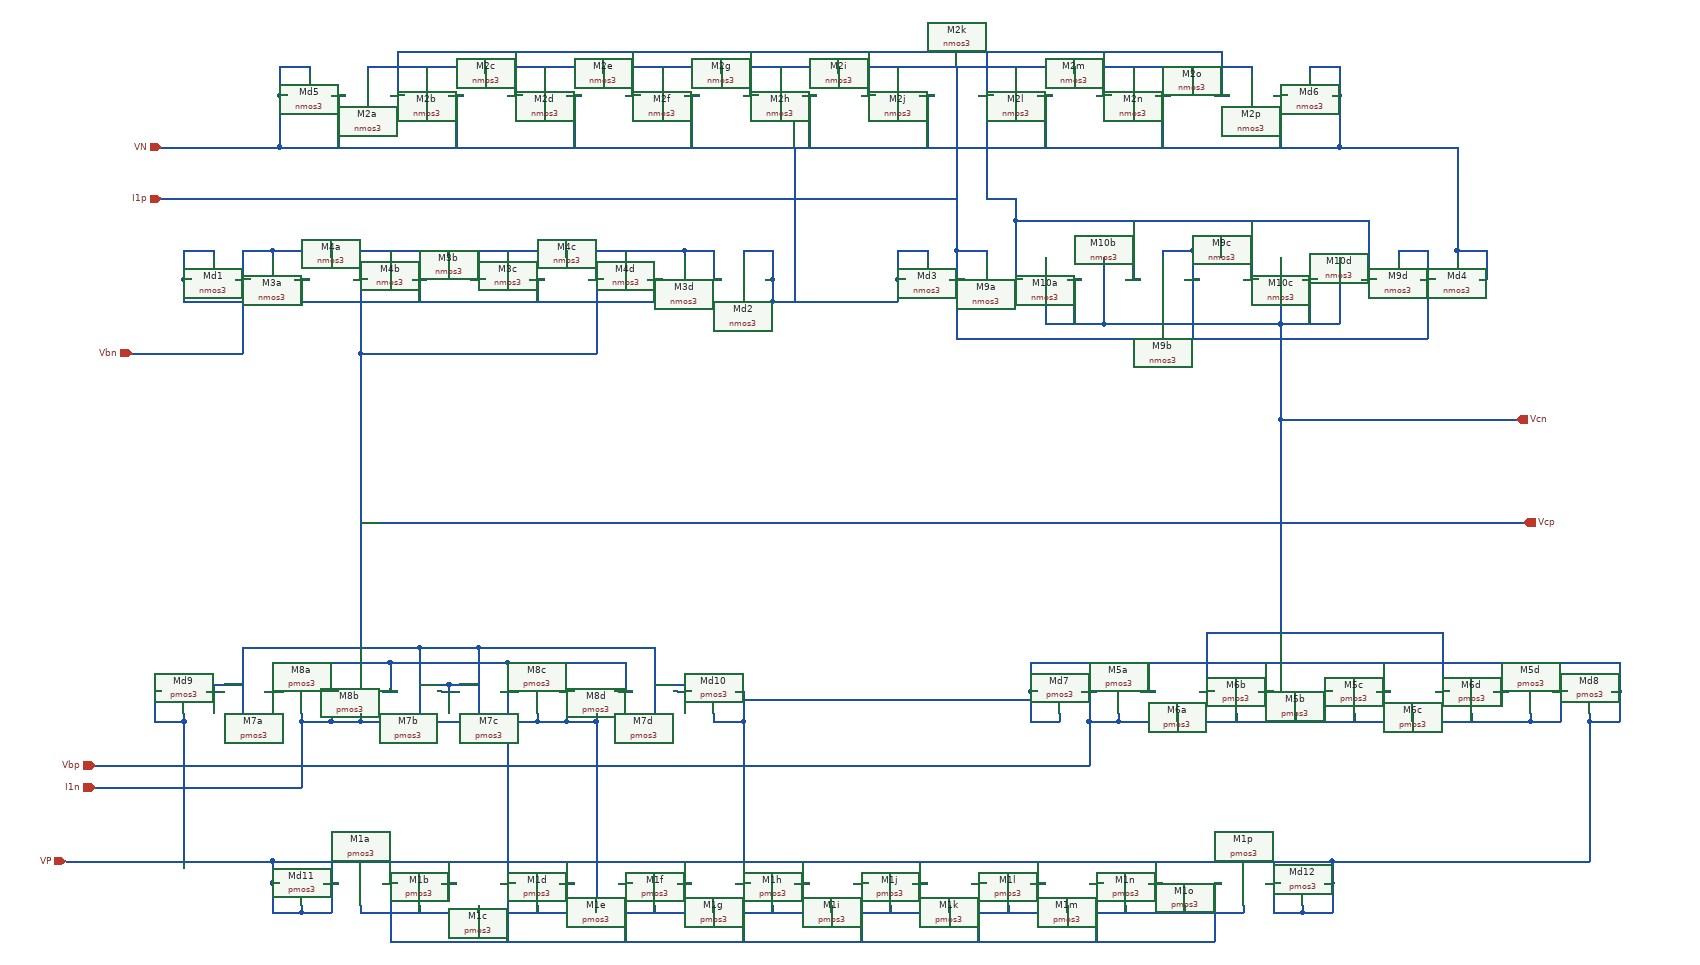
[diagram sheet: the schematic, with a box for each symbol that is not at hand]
v {xschem version=2.9.9 file_version=1.2 }
G {}
K {}
V {}
S {}
E {}
N 580 -1780 600 -1780 { lab=I1p}
N 660 -1780 680 -1780 { lab=Vcp}
N 740 -1780 760 -1780 { lab=I1p}
N 820 -1780 840 -1780 { lab=Vbn}
N 900 -1780 920 -1780 { lab=I1p}
N 980 -1780 1000 -1780 { lab=Vcp}
N 1060 -1780 1080 -1780 { lab=I1p}
N 550 -1820 550 -1810 { lab=Vbn}
N 630 -1820 630 -1810 { lab=Vbn}
N 710 -1820 710 -1810 { lab=Vbn}
N 790 -1820 790 -1810 { lab=Vbn}
N 870 -1820 870 -1810 { lab=Vbn}
N 950 -1820 950 -1810 { lab=Vbn}
N 1030 -1820 1030 -1810 { lab=Vbn}
N 1110 -1820 1110 -1810 { lab=Vbn}
N 550 -1820 1110 -1820 { lab=Vbn}
N 500 -1780 520 -1780 { lab=Vbn}
N 510 -1820 510 -1780 { lab=Vbn}
N 510 -1820 550 -1820 { lab=Vbn}
N 590 -1780 590 -1750 { lab=I1p}
N 750 -1780 750 -1750 { lab=I1p}
N 910 -1780 910 -1750 { lab=I1p}
N 830 -1820 830 -1780 { lab=Vbn}
N 1070 -1780 1070 -1750 { lab=I1p}
N 1140 -1780 1160 -1780 { lab=Vbn}
N 1150 -1820 1150 -1780 { lab=Vbn}
N 1110 -1820 1150 -1820 { lab=Vbn}
N 1190 -1820 1190 -1810 { lab=I1p}
N 1190 -1820 1230 -1820 { lab=I1p}
N 1230 -1820 1230 -1780 { lab=I1p}
N 1220 -1780 1230 -1780 { lab=I1p}
N 430 -1780 440 -1780 { lab=I1p}
N 430 -1820 430 -1780 { lab=I1p}
N 430 -1820 470 -1820 { lab=I1p}
N 470 -1820 470 -1810 { lab=I1p}
N 430 -1780 430 -1750 { lab=I1p}
N 1230 -1780 1230 -1750 { lab=I1p}
N 1550 -1780 1570 -1780 { lab=#net1}
N 1630 -1780 1650 -1780 { lab=Vcn}
N 1710 -1780 1730 -1780 { lab=#net1}
N 1790 -1780 1810 -1780 { lab=I1p}
N 1870 -1780 1890 -1780 { lab=#net1}
N 1950 -1780 1970 -1780 { lab=Vcn}
N 2030 -1780 2050 -1780 { lab=#net1}
N 1470 -1780 1490 -1780 { lab=I1p}
N 2110 -1780 2130 -1780 { lab=I1p}
N 2160 -1820 2160 -1810 { lab=I1p}
N 2160 -1820 2200 -1820 { lab=I1p}
N 2200 -1820 2200 -1780 { lab=I1p}
N 2190 -1780 2200 -1780 { lab=I1p}
N 1400 -1780 1410 -1780 { lab=I1p}
N 1400 -1820 1400 -1780 { lab=I1p}
N 1400 -1820 1440 -1820 { lab=I1p}
N 1440 -1820 1440 -1810 { lab=I1p}
N 1400 -1780 1400 -1750 { lab=I1p}
N 670 -1780 670 -1680 { lab=Vcp}
N 990 -1780 990 -1680 { lab=Vcp}
N 670 -1680 990 -1680 { lab=Vcp}
N 1560 -1860 2040 -1860 { lab=#net1}
N 1560 -1890 1560 -1860 { lab=#net1}
N 1520 -1820 1520 -1810 { lab=I1p}
N 1760 -1820 1760 -1810 { lab=I1p}
N 1840 -1820 1840 -1810 { lab=I1p}
N 2080 -1820 2080 -1810 { lab=I1p}
N 1600 -1810 1600 -1720 { lab=Vcn}
N 1600 -1720 1680 -1720 { lab=Vcn}
N 1680 -1810 1680 -1720 { lab=Vcn}
N 1920 -1810 1920 -1720 { lab=Vcn}
N 1920 -1720 2000 -1720 { lab=Vcn}
N 2000 -1810 2000 -1720 { lab=Vcn}
N 1680 -1720 1920 -1720 { lab=Vcn}
N 1920 -1720 1920 -1590 { lab=Vcn}
N 1920 -1590 2240 -1590 { lab=Vcn}
N 1560 -1860 1560 -1780 { lab=#net1}
N 1720 -1860 1720 -1780 { lab=#net1}
N 1880 -1860 1880 -1780 { lab=#net1}
N 2040 -1860 2040 -1780 { lab=#net1}
N 710 -2030 730 -2030 { lab=#net1}
N 790 -2030 810 -2030 { lab=I1p}
N 870 -2030 890 -2030 { lab=#net1}
N 950 -2030 970 -2030 { lab=I1p}
N 1030 -2030 1050 -2030 { lab=#net1}
N 1110 -2030 1130 -2030 { lab=I1p}
N 1190 -2030 1210 -2030 { lab=#net1}
N 1270 -2030 1290 -2030 { lab=I1p}
N 1350 -2030 1370 -2030 { lab=#net1}
N 1430 -2030 1450 -2030 { lab=I1p}
N 1510 -2030 1530 -2030 { lab=#net1}
N 1590 -2030 1610 -2030 { lab=I1p}
N 1670 -2030 1690 -2030 { lab=#net1}
N 1750 -2030 1770 -2030 { lab=I1p}
N 1830 -2030 1850 -2030 { lab=#net1}
N 680 -2070 680 -2060 { lab=I1p}
N 760 -2070 760 -2060 { lab=I1p}
N 840 -2070 840 -2060 { lab=I1p}
N 920 -2070 920 -2060 { lab=I1p}
N 1000 -2070 1000 -2060 { lab=I1p}
N 1080 -2070 1080 -2060 { lab=I1p}
N 1160 -2070 1160 -2060 { lab=I1p}
N 1240 -2070 1240 -2060 { lab=I1p}
N 1320 -2070 1320 -2060 { lab=I1p}
N 1400 -2070 1400 -2060 { lab=I1p}
N 1480 -2070 1480 -2060 { lab=I1p}
N 1560 -2070 1560 -2060 { lab=I1p}
N 1640 -2070 1640 -2060 { lab=I1p}
N 1720 -2070 1720 -2060 { lab=I1p}
N 1800 -2070 1800 -2060 { lab=I1p}
N 1880 -2070 1880 -2060 { lab=I1p}
N 680 -2070 1880 -2070 { lab=I1p}
N 640 -2030 640 -1960 { lab=I1p}
N 960 -2030 960 -1960 { lab=I1p}
N 1120 -2030 1120 -1960 { lab=I1p}
N 1280 -2030 1280 -1960 { lab=I1p}
N 1440 -2030 1440 -1960 { lab=I1p}
N 1600 -2030 1600 -1960 { lab=I1p}
N 1760 -2030 1760 -1960 { lab=I1p}
N 630 -2030 650 -2030 { lab=I1p}
N 600 -2070 600 -2060 { lab=I1p}
N 560 -2070 600 -2070 { lab=I1p}
N 560 -2070 560 -2030 { lab=I1p}
N 560 -2030 570 -2030 { lab=I1p}
N 560 -2030 560 -1960 { lab=I1p}
N 1910 -2030 1930 -2030 { lab=I1p}
N 1960 -2070 1960 -2060 { lab=I1p}
N 1960 -2070 2000 -2070 { lab=I1p}
N 2000 -2070 2000 -2030 { lab=I1p}
N 1990 -2030 2000 -2030 { lab=I1p}
N 2000 -2030 2000 -1960 { lab=I1p}
N 1480 -1700 2120 -1700 { lab=I1p}
N 1800 -1780 1800 -1700 { lab=I1p}
N 1480 -1780 1480 -1700 { lab=I1p}
N 2120 -1780 2120 -1700 { lab=I1p}
N 1760 -1820 1800 -1820 { lab=I1p}
N 1800 -1820 1800 -1780 { lab=I1p}
N 1800 -1820 1840 -1820 { lab=I1p}
N 2080 -1820 2120 -1820 { lab=I1p}
N 2120 -1820 2120 -1780 { lab=I1p}
N 1480 -1820 1520 -1820 { lab=I1p}
N 1480 -1820 1480 -1780 { lab=I1p}
N 1480 -2060 1480 -1910 { lab=I1p}
N 1640 -1780 1640 -1720 { lab=Vcn}
N 1960 -1780 1960 -1720 { lab=Vcn}
N 1730 -1220 1750 -1220 { lab=VP}
N 1700 -1190 1700 -1180 { lab=Vbp}
N 1780 -1190 1780 -1180 { lab=Vbp}
N 1810 -1220 1830 -1220 { lab=Vcn}
N 1890 -1220 1910 -1220 { lab=VP}
N 1860 -1190 1860 -1180 { lab=Vbp}
N 1940 -1190 1940 -1180 { lab=Vbp}
N 1970 -1220 1990 -1220 { lab=Vbp}
N 2050 -1220 2070 -1220 { lab=VP}
N 2020 -1190 2020 -1180 { lab=Vbp}
N 2100 -1190 2100 -1180 { lab=Vbp}
N 2130 -1220 2150 -1220 { lab=Vcn}
N 2210 -1220 2230 -1220 { lab=VP}
N 2180 -1190 2180 -1180 { lab=Vbp}
N 2260 -1190 2260 -1180 { lab=Vbp}
N 2290 -1220 2310 -1220 { lab=Vbp}
N 1700 -1180 2260 -1180 { lab=Vbp}
N 1650 -1220 1670 -1220 { lab=Vbp}
N 1580 -1220 1590 -1220 { lab=VP}
N 2370 -1220 2380 -1220 { lab=VP}
N 1580 -1220 1580 -1180 { lab=VP}
N 1580 -1180 1620 -1180 { lab=VP}
N 1620 -1190 1620 -1180 { lab=VP}
N 1580 -1260 1580 -1220 { lab=VP}
N 2340 -1190 2340 -1180 { lab=VP}
N 2340 -1180 2380 -1180 { lab=VP}
N 2380 -1220 2380 -1180 { lab=VP}
N 2380 -1260 2380 -1220 { lab=VP}
N 1740 -1260 1740 -1220 { lab=VP}
N 1900 -1260 1900 -1220 { lab=VP}
N 1820 -1300 1820 -1220 { lab=Vcn}
N 2060 -1260 2060 -1220 { lab=VP}
N 2140 -1300 2140 -1220 { lab=Vcn}
N 2220 -1260 2220 -1220 { lab=VP}
N 1660 -1220 1660 -1180 { lab=Vbp}
N 1660 -1180 1700 -1180 { lab=Vbp}
N 2300 -1220 2300 -1180 { lab=Vbp}
N 2260 -1180 2300 -1180 { lab=Vbp}
N 1980 -1220 1980 -1180 { lab=Vbp}
N 1660 -1180 1660 -1120 { lab=Vbp}
N 540 -1220 560 -1220 { lab=#net2}
N 620 -1220 640 -1220 { lab=I1n}
N 700 -1220 720 -1220 { lab=#net2}
N 780 -1220 800 -1220 { lab=Vcp}
N 860 -1220 880 -1220 { lab=#net2}
N 940 -1220 960 -1220 { lab=I1n}
N 1020 -1220 1040 -1220 { lab=#net2}
N 1100 -1220 1120 -1220 { lab=Vcp}
N 460 -1220 480 -1220 { lab=Vcp}
N 390 -1220 400 -1220 { lab=VP}
N 1180 -1220 1190 -1220 { lab=VP}
N 390 -1220 390 -1180 { lab=VP}
N 390 -1180 430 -1180 { lab=VP}
N 430 -1190 430 -1180 { lab=VP}
N 1150 -1190 1150 -1180 { lab=VP}
N 1150 -1180 1190 -1180 { lab=VP}
N 1190 -1220 1190 -1180 { lab=VP}
N 590 -1190 590 -1180 { lab=I1n}
N 910 -1190 910 -1180 { lab=I1n}
N 910 -1180 950 -1180 { lab=I1n}
N 990 -1190 990 -1180 { lab=I1n}
N 950 -1180 990 -1180 { lab=I1n}
N 670 -1190 670 -1180 { lab=I1n}
N 630 -1180 670 -1180 { lab=I1n}
N 590 -1180 630 -1180 { lab=I1n}
N 510 -1280 510 -1190 { lab=Vcp}
N 510 -1280 750 -1280 { lab=Vcp}
N 750 -1280 750 -1190 { lab=Vcp}
N 830 -1280 830 -1190 { lab=Vcp}
N 750 -1280 830 -1280 { lab=Vcp}
N 1070 -1280 1070 -1190 { lab=Vcp}
N 830 -1280 1070 -1280 { lab=Vcp}
N 470 -1230 470 -1220 { lab=Vcp}
N 470 -1230 510 -1230 { lab=Vcp}
N 790 -1230 790 -1220 { lab=Vcp}
N 750 -1230 790 -1230 { lab=Vcp}
N 790 -1230 830 -1230 { lab=Vcp}
N 1110 -1230 1110 -1220 { lab=Vcp}
N 1070 -1230 1110 -1230 { lab=Vcp}
N 710 -1260 710 -1220 { lab=#net2}
N 550 -1260 710 -1260 { lab=#net2}
N 550 -1260 550 -1220 { lab=#net2}
N 870 -1260 870 -1220 { lab=#net2}
N 870 -1260 1030 -1260 { lab=#net2}
N 1030 -1260 1030 -1220 { lab=#net2}
N 710 -1260 870 -1260 { lab=#net2}
N 670 -930 670 -920 { lab=I1n}
N 700 -960 720 -960 { lab=#net2}
N 750 -930 750 -920 { lab=I1n}
N 780 -960 800 -960 { lab=VP}
N 830 -930 830 -920 { lab=I1n}
N 860 -960 880 -960 { lab=#net2}
N 910 -930 910 -920 { lab=I1n}
N 940 -960 960 -960 { lab=VP}
N 990 -930 990 -920 { lab=I1n}
N 1020 -960 1040 -960 { lab=#net2}
N 1070 -930 1070 -920 { lab=I1n}
N 1100 -960 1120 -960 { lab=VP}
N 1150 -930 1150 -920 { lab=I1n}
N 1180 -960 1200 -960 { lab=#net2}
N 1230 -930 1230 -920 { lab=I1n}
N 1260 -960 1280 -960 { lab=VP}
N 1310 -930 1310 -920 { lab=I1n}
N 1340 -960 1360 -960 { lab=#net2}
N 1390 -930 1390 -920 { lab=I1n}
N 1420 -960 1440 -960 { lab=VP}
N 1470 -930 1470 -920 { lab=I1n}
N 1500 -960 1520 -960 { lab=#net2}
N 1550 -930 1550 -920 { lab=I1n}
N 1580 -960 1600 -960 { lab=VP}
N 1630 -930 1630 -920 { lab=I1n}
N 1660 -960 1680 -960 { lab=#net2}
N 1710 -930 1710 -920 { lab=I1n}
N 1740 -960 1760 -960 { lab=VP}
N 1790 -930 1790 -920 { lab=I1n}
N 1820 -960 1840 -960 { lab=#net2}
N 1870 -930 1870 -920 { lab=I1n}
N 1900 -960 1920 -960 { lab=VP}
N 670 -920 1870 -920 { lab=I1n}
N 620 -960 640 -960 { lab=VP}
N 710 -960 710 -880 { lab=#net2}
N 790 -990 790 -960 { lab=VP}
N 870 -960 870 -880 { lab=#net2}
N 950 -990 950 -960 { lab=VP}
N 1030 -960 1030 -880 { lab=#net2}
N 1110 -990 1110 -960 { lab=VP}
N 1190 -960 1190 -880 { lab=#net2}
N 1270 -990 1270 -960 { lab=VP}
N 1350 -960 1350 -880 { lab=#net2}
N 1430 -990 1430 -960 { lab=VP}
N 1510 -960 1510 -880 { lab=#net2}
N 1590 -990 1590 -960 { lab=VP}
N 1670 -960 1670 -880 { lab=#net2}
N 1750 -990 1750 -960 { lab=VP}
N 1830 -960 1830 -880 { lab=#net2}
N 630 -1220 630 -1180 { lab=I1n}
N 950 -1220 950 -1180 { lab=I1n}
N 670 -1180 910 -1180 { lab=I1n}
N 990 -1180 990 -1110 { lab=I1n}
N 710 -880 1830 -880 { lab=#net2}
N 310 -1090 590 -1090 { lab=I1n}
N 400 -1890 1480 -1890 { lab=I1p}
N 1950 -930 1950 -920 { lab=VP}
N 1950 -920 1980 -920 { lab=VP}
N 1980 -920 1990 -920 { lab=VP}
N 1990 -960 1990 -920 { lab=VP}
N 1980 -960 1990 -960 { lab=VP}
N 1990 -990 1990 -960 { lab=VP}
N 590 -930 590 -920 { lab=VP}
N 550 -920 590 -920 { lab=VP}
N 550 -960 550 -920 { lab=VP}
N 550 -960 560 -960 { lab=VP}
N 550 -990 550 -960 { lab=VP}
N 670 -1450 2250 -1450 { lab=Vcp}
N 510 -1780 510 -1680 { lab=Vbn}
N 360 -1680 510 -1680 { lab=Vbn}
N 310 -1120 1660 -1120 { lab=Vbp}
N 670 -1680 670 -1670 { lab=Vcp}
N 630 -960 630 -920 { lab=VP}
N 590 -920 620 -920 { lab=VP}
N 620 -920 630 -920 { lab=VP}
N 1910 -920 1950 -920 { lab=VP}
N 1910 -960 1910 -920 { lab=VP}
N 800 -2030 800 -1960 { lab=I1p}
N 1920 -2030 1920 -1960 { lab=I1p}
N 1840 -2090 1840 -2030 { lab=#net1}
N 1680 -2090 1680 -2030 { lab=#net1}
N 720 -2090 720 -2030 { lab=#net1}
N 880 -2090 880 -2030 { lab=#net1}
N 1040 -2090 1040 -2030 { lab=#net1}
N 1200 -2090 1200 -2030 { lab=#net1}
N 1360 -2090 1360 -2030 { lab=#net1}
N 1520 -2090 1520 -2030 { lab=#net1}
N 720 -2090 1840 -2090 { lab=#net1}
N 1910 -990 1910 -960 { lab=VP}
N 630 -990 630 -960 { lab=VP}
N 560 -1960 2000 -1960 { lab=I1p}
N 480 -1960 560 -1960 { lab=I1p}
N 430 -1750 1230 -1750 { lab=I1p}
N 1230 -1750 1270 -1750 { lab=I1p}
N 1270 -1750 1400 -1750 { lab=I1p}
N 2000 -1960 2160 -1960 { lab=I1p}
N 550 -990 1990 -990 { lab=VP}
N 280 -990 550 -990 { lab=VP}
N 1190 -1210 1580 -1210 { lab=VP}
N 1990 -990 2340 -990 { lab=VP}
N 1820 -1300 2140 -1300 { lab=Vcn}
N 1580 -1260 2380 -1260 { lab=VP}
N 400 -1960 480 -1960 { lab=I1p}
N 270 -990 280 -990 { lab=VP}
N 670 -1670 670 -1280 {}
N 1920 -1590 1920 -1300 {}
N 1260 -1960 1260 -1930 {}
N 1480 -1840 1480 -1820 {}
N 1520 -1890 1560 -1890 {}
N 1520 -1900 1520 -1890 {}
N 1520 -2030 1520 -1930 {}
N 2160 -1900 2160 -1820 {}
N 2160 -1960 2160 -1930 {}
N 1260 -1930 1260 -1750 {}
N 1480 -1910 1480 -1840 {}
N 1520 -1930 1520 -1900 {}
N 2160 -1930 2160 -1900 {}
N 2340 -1020 2340 -990 {}
N 2340 -1180 2340 -1150 {}
N 1190 -1010 1190 -990 {}
N 1190 -1180 1190 -1100 {}
N 990 -1010 990 -930 {}
N 870 -1220 870 -1110 {}
N 870 -1010 870 -960 {}
N 430 -1010 430 -990 {}
N 430 -1180 430 -1070 {}
N 590 -1180 590 -1090 {}
N 2340 -1150 2340 -1020 {}
N 1190 -1100 1190 -1010 {}
N 990 -1110 990 -1010 {}
N 870 -1110 870 -1010 {}
N 430 -1070 430 -1010 {}
C {madvlsi/nmos3.sym} 550 -1780 1 0 {name=M3a
L=0.5
W=3
body=GND
nf=1
mult=1
ad="'int((nf+1)/2) * W/nf * 0.29'" 
pd="'2*int((nf+1)/2) * (W/nf + 0.29)'"
as="'int((nf+2)/2) * W/nf * 0.29'" 
ps="'2*int((nf+2)/2) * (W/nf + 0.29)'"
nrd="'0.29 / W'" nrs="'0.29 / W'"
sa=0 sb=0 sd=0
model=nfet_01v8
spiceprefix=X
}
C {madvlsi/nmos3.sym} 630 -1780 1 0 {name=M4a
L=0.5
W=3
body=GND
nf=1
mult=1
ad="'int((nf+1)/2) * W/nf * 0.29'" 
pd="'2*int((nf+1)/2) * (W/nf + 0.29)'"
as="'int((nf+2)/2) * W/nf * 0.29'" 
ps="'2*int((nf+2)/2) * (W/nf + 0.29)'"
nrd="'0.29 / W'" nrs="'0.29 / W'"
sa=0 sb=0 sd=0
model=nfet_01v8
spiceprefix=X
}
C {madvlsi/nmos3.sym} 710 -1780 1 0 {name=M4b
L=0.5
W=3
body=GND
nf=1
mult=1
ad="'int((nf+1)/2) * W/nf * 0.29'" 
pd="'2*int((nf+1)/2) * (W/nf + 0.29)'"
as="'int((nf+2)/2) * W/nf * 0.29'" 
ps="'2*int((nf+2)/2) * (W/nf + 0.29)'"
nrd="'0.29 / W'" nrs="'0.29 / W'"
sa=0 sb=0 sd=0
model=nfet_01v8
spiceprefix=X
}
C {madvlsi/nmos3.sym} 790 -1780 1 0 {name=M3b
L=0.5
W=3
body=GND
nf=1
mult=1
ad="'int((nf+1)/2) * W/nf * 0.29'" 
pd="'2*int((nf+1)/2) * (W/nf + 0.29)'"
as="'int((nf+2)/2) * W/nf * 0.29'" 
ps="'2*int((nf+2)/2) * (W/nf + 0.29)'"
nrd="'0.29 / W'" nrs="'0.29 / W'"
sa=0 sb=0 sd=0
model=nfet_01v8
spiceprefix=X
}
C {madvlsi/nmos3.sym} 870 -1780 1 0 {name=M3c
L=0.5
W=3
body=GND
nf=1
mult=1
ad="'int((nf+1)/2) * W/nf * 0.29'" 
pd="'2*int((nf+1)/2) * (W/nf + 0.29)'"
as="'int((nf+2)/2) * W/nf * 0.29'" 
ps="'2*int((nf+2)/2) * (W/nf + 0.29)'"
nrd="'0.29 / W'" nrs="'0.29 / W'"
sa=0 sb=0 sd=0
model=nfet_01v8
spiceprefix=X
}
C {madvlsi/nmos3.sym} 950 -1780 1 0 {name=M4c
L=0.5
W=3
body=GND
nf=1
mult=1
ad="'int((nf+1)/2) * W/nf * 0.29'" 
pd="'2*int((nf+1)/2) * (W/nf + 0.29)'"
as="'int((nf+2)/2) * W/nf * 0.29'" 
ps="'2*int((nf+2)/2) * (W/nf + 0.29)'"
nrd="'0.29 / W'" nrs="'0.29 / W'"
sa=0 sb=0 sd=0
model=nfet_01v8
spiceprefix=X
}
C {madvlsi/nmos3.sym} 1030 -1780 1 0 {name=M4d
L=0.5
W=3
body=GND
nf=1
mult=1
ad="'int((nf+1)/2) * W/nf * 0.29'" 
pd="'2*int((nf+1)/2) * (W/nf + 0.29)'"
as="'int((nf+2)/2) * W/nf * 0.29'" 
ps="'2*int((nf+2)/2) * (W/nf + 0.29)'"
nrd="'0.29 / W'" nrs="'0.29 / W'"
sa=0 sb=0 sd=0
model=nfet_01v8
spiceprefix=X
}
C {madvlsi/nmos3.sym} 1110 -1780 1 0 {name=M3d
L=0.5
W=3
body=GND
nf=1
mult=1
ad="'int((nf+1)/2) * W/nf * 0.29'" 
pd="'2*int((nf+1)/2) * (W/nf + 0.29)'"
as="'int((nf+2)/2) * W/nf * 0.29'" 
ps="'2*int((nf+2)/2) * (W/nf + 0.29)'"
nrd="'0.29 / W'" nrs="'0.29 / W'"
sa=0 sb=0 sd=0
model=nfet_01v8
spiceprefix=X
}
C {madvlsi/nmos3.sym} 1190 -1780 1 0 {name=Md2
L=0.5
W=3
body=GND
nf=1
mult=1
ad="'int((nf+1)/2) * W/nf * 0.29'" 
pd="'2*int((nf+1)/2) * (W/nf + 0.29)'"
as="'int((nf+2)/2) * W/nf * 0.29'" 
ps="'2*int((nf+2)/2) * (W/nf + 0.29)'"
nrd="'0.29 / W'" nrs="'0.29 / W'"
sa=0 sb=0 sd=0
model=nfet_01v8
spiceprefix=X
}
C {madvlsi/nmos3.sym} 470 -1780 1 0 {name=Md1
L=0.5
W=3
body=GND
nf=1
mult=1
ad="'int((nf+1)/2) * W/nf * 0.29'" 
pd="'2*int((nf+1)/2) * (W/nf + 0.29)'"
as="'int((nf+2)/2) * W/nf * 0.29'" 
ps="'2*int((nf+2)/2) * (W/nf + 0.29)'"
nrd="'0.29 / W'" nrs="'0.29 / W'"
sa=0 sb=0 sd=0
model=nfet_01v8
spiceprefix=X
}
C {madvlsi/nmos3.sym} 1520 -1780 1 0 {name=M9a
L=0.5
W=3
body=GND
nf=1
mult=1
ad="'int((nf+1)/2) * W/nf * 0.29'" 
pd="'2*int((nf+1)/2) * (W/nf + 0.29)'"
as="'int((nf+2)/2) * W/nf * 0.29'" 
ps="'2*int((nf+2)/2) * (W/nf + 0.29)'"
nrd="'0.29 / W'" nrs="'0.29 / W'"
sa=0 sb=0 sd=0
model=nfet_01v8
spiceprefix=X
}
C {madvlsi/nmos3.sym} 1600 -1780 1 0 {name=M10a
L=0.5
W=3
body=GND
nf=1
mult=1
ad="'int((nf+1)/2) * W/nf * 0.29'" 
pd="'2*int((nf+1)/2) * (W/nf + 0.29)'"
as="'int((nf+2)/2) * W/nf * 0.29'" 
ps="'2*int((nf+2)/2) * (W/nf + 0.29)'"
nrd="'0.29 / W'" nrs="'0.29 / W'"
sa=0 sb=0 sd=0
model=nfet_01v8
spiceprefix=X
}
C {madvlsi/nmos3.sym} 1680 -1780 1 0 {name=M10b
L=0.5
W=3
body=GND
nf=1
mult=1
ad="'int((nf+1)/2) * W/nf * 0.29'" 
pd="'2*int((nf+1)/2) * (W/nf + 0.29)'"
as="'int((nf+2)/2) * W/nf * 0.29'" 
ps="'2*int((nf+2)/2) * (W/nf + 0.29)'"
nrd="'0.29 / W'" nrs="'0.29 / W'"
sa=0 sb=0 sd=0
model=nfet_01v8
spiceprefix=X
}
C {madvlsi/nmos3.sym} 1760 -1780 1 0 {name=M9b
L=0.5
W=3
body=GND
nf=1
mult=1
ad="'int((nf+1)/2) * W/nf * 0.29'" 
pd="'2*int((nf+1)/2) * (W/nf + 0.29)'"
as="'int((nf+2)/2) * W/nf * 0.29'" 
ps="'2*int((nf+2)/2) * (W/nf + 0.29)'"
nrd="'0.29 / W'" nrs="'0.29 / W'"
sa=0 sb=0 sd=0
model=nfet_01v8
spiceprefix=X
}
C {madvlsi/nmos3.sym} 1840 -1780 1 0 {name=M9c
L=0.5
W=3
body=GND
nf=1
mult=1
ad="'int((nf+1)/2) * W/nf * 0.29'" 
pd="'2*int((nf+1)/2) * (W/nf + 0.29)'"
as="'int((nf+2)/2) * W/nf * 0.29'" 
ps="'2*int((nf+2)/2) * (W/nf + 0.29)'"
nrd="'0.29 / W'" nrs="'0.29 / W'"
sa=0 sb=0 sd=0
model=nfet_01v8
spiceprefix=X
}
C {madvlsi/nmos3.sym} 1920 -1780 1 0 {name=M10c
L=0.5
W=3
body=GND
nf=1
mult=1
ad="'int((nf+1)/2) * W/nf * 0.29'" 
pd="'2*int((nf+1)/2) * (W/nf + 0.29)'"
as="'int((nf+2)/2) * W/nf * 0.29'" 
ps="'2*int((nf+2)/2) * (W/nf + 0.29)'"
nrd="'0.29 / W'" nrs="'0.29 / W'"
sa=0 sb=0 sd=0
model=nfet_01v8
spiceprefix=X
}
C {madvlsi/nmos3.sym} 2000 -1780 1 0 {name=M10d
L=0.5
W=3
body=GND
nf=1
mult=1
ad="'int((nf+1)/2) * W/nf * 0.29'" 
pd="'2*int((nf+1)/2) * (W/nf + 0.29)'"
as="'int((nf+2)/2) * W/nf * 0.29'" 
ps="'2*int((nf+2)/2) * (W/nf + 0.29)'"
nrd="'0.29 / W'" nrs="'0.29 / W'"
sa=0 sb=0 sd=0
model=nfet_01v8
spiceprefix=X
}
C {madvlsi/nmos3.sym} 2080 -1780 1 0 {name=M9d
L=0.5
W=3
body=GND
nf=1
mult=1
ad="'int((nf+1)/2) * W/nf * 0.29'" 
pd="'2*int((nf+1)/2) * (W/nf + 0.29)'"
as="'int((nf+2)/2) * W/nf * 0.29'" 
ps="'2*int((nf+2)/2) * (W/nf + 0.29)'"
nrd="'0.29 / W'" nrs="'0.29 / W'"
sa=0 sb=0 sd=0
model=nfet_01v8
spiceprefix=X
}
C {madvlsi/nmos3.sym} 2160 -1780 1 0 {name=Md4
L=0.5
W=3
body=GND
nf=1
mult=1
ad="'int((nf+1)/2) * W/nf * 0.29'" 
pd="'2*int((nf+1)/2) * (W/nf + 0.29)'"
as="'int((nf+2)/2) * W/nf * 0.29'" 
ps="'2*int((nf+2)/2) * (W/nf + 0.29)'"
nrd="'0.29 / W'" nrs="'0.29 / W'"
sa=0 sb=0 sd=0
model=nfet_01v8
spiceprefix=X
}
C {madvlsi/nmos3.sym} 1440 -1780 1 0 {name=Md3
L=0.5
W=3
body=GND
nf=1
mult=1
ad="'int((nf+1)/2) * W/nf * 0.29'" 
pd="'2*int((nf+1)/2) * (W/nf + 0.29)'"
as="'int((nf+2)/2) * W/nf * 0.29'" 
ps="'2*int((nf+2)/2) * (W/nf + 0.29)'"
nrd="'0.29 / W'" nrs="'0.29 / W'"
sa=0 sb=0 sd=0
model=nfet_01v8
spiceprefix=X
}
C {madvlsi/nmos3.sym} 680 -2030 1 0 {name=M2a
L=0.5
W=0.75
body=GND
nf=1
mult=1
ad="'int((nf+1)/2) * W/nf * 0.29'" 
pd="'2*int((nf+1)/2) * (W/nf + 0.29)'"
as="'int((nf+2)/2) * W/nf * 0.29'" 
ps="'2*int((nf+2)/2) * (W/nf + 0.29)'"
nrd="'0.29 / W'" nrs="'0.29 / W'"
sa=0 sb=0 sd=0
model=nfet_01v8
spiceprefix=X
}
C {madvlsi/nmos3.sym} 760 -2030 1 0 {name=M2b
L=0.5
W=0.75
body=GND
nf=1
mult=1
ad="'int((nf+1)/2) * W/nf * 0.29'" 
pd="'2*int((nf+1)/2) * (W/nf + 0.29)'"
as="'int((nf+2)/2) * W/nf * 0.29'" 
ps="'2*int((nf+2)/2) * (W/nf + 0.29)'"
nrd="'0.29 / W'" nrs="'0.29 / W'"
sa=0 sb=0 sd=0
model=nfet_01v8
spiceprefix=X
}
C {madvlsi/nmos3.sym} 840 -2030 1 0 {name=M2c
L=0.5
W=0.75
body=GND
nf=1
mult=1
ad="'int((nf+1)/2) * W/nf * 0.29'" 
pd="'2*int((nf+1)/2) * (W/nf + 0.29)'"
as="'int((nf+2)/2) * W/nf * 0.29'" 
ps="'2*int((nf+2)/2) * (W/nf + 0.29)'"
nrd="'0.29 / W'" nrs="'0.29 / W'"
sa=0 sb=0 sd=0
model=nfet_01v8
spiceprefix=X
}
C {madvlsi/nmos3.sym} 920 -2030 1 0 {name=M2d
L=0.5
W=0.75
body=GND
nf=1
mult=1
ad="'int((nf+1)/2) * W/nf * 0.29'" 
pd="'2*int((nf+1)/2) * (W/nf + 0.29)'"
as="'int((nf+2)/2) * W/nf * 0.29'" 
ps="'2*int((nf+2)/2) * (W/nf + 0.29)'"
nrd="'0.29 / W'" nrs="'0.29 / W'"
sa=0 sb=0 sd=0
model=nfet_01v8
spiceprefix=X
}
C {madvlsi/nmos3.sym} 1000 -2030 1 0 {name=M2e
L=0.5
W=0.75
body=GND
nf=1
mult=1
ad="'int((nf+1)/2) * W/nf * 0.29'" 
pd="'2*int((nf+1)/2) * (W/nf + 0.29)'"
as="'int((nf+2)/2) * W/nf * 0.29'" 
ps="'2*int((nf+2)/2) * (W/nf + 0.29)'"
nrd="'0.29 / W'" nrs="'0.29 / W'"
sa=0 sb=0 sd=0
model=nfet_01v8
spiceprefix=X
}
C {madvlsi/nmos3.sym} 1080 -2030 1 0 {name=M2f
L=0.5
W=0.75
body=GND
nf=1
mult=1
ad="'int((nf+1)/2) * W/nf * 0.29'" 
pd="'2*int((nf+1)/2) * (W/nf + 0.29)'"
as="'int((nf+2)/2) * W/nf * 0.29'" 
ps="'2*int((nf+2)/2) * (W/nf + 0.29)'"
nrd="'0.29 / W'" nrs="'0.29 / W'"
sa=0 sb=0 sd=0
model=nfet_01v8
spiceprefix=X
}
C {madvlsi/nmos3.sym} 1160 -2030 1 0 {name=M2g
L=0.5
W=0.75
body=GND
nf=1
mult=1
ad="'int((nf+1)/2) * W/nf * 0.29'" 
pd="'2*int((nf+1)/2) * (W/nf + 0.29)'"
as="'int((nf+2)/2) * W/nf * 0.29'" 
ps="'2*int((nf+2)/2) * (W/nf + 0.29)'"
nrd="'0.29 / W'" nrs="'0.29 / W'"
sa=0 sb=0 sd=0
model=nfet_01v8
spiceprefix=X
}
C {madvlsi/nmos3.sym} 1240 -2030 1 0 {name=M2h
L=0.5
W=0.75
body=GND
nf=1
mult=1
ad="'int((nf+1)/2) * W/nf * 0.29'" 
pd="'2*int((nf+1)/2) * (W/nf + 0.29)'"
as="'int((nf+2)/2) * W/nf * 0.29'" 
ps="'2*int((nf+2)/2) * (W/nf + 0.29)'"
nrd="'0.29 / W'" nrs="'0.29 / W'"
sa=0 sb=0 sd=0
model=nfet_01v8
spiceprefix=X
}
C {madvlsi/nmos3.sym} 1320 -2030 1 0 {name=M2i
L=0.5
W=0.75
body=GND
nf=1
mult=1
ad="'int((nf+1)/2) * W/nf * 0.29'" 
pd="'2*int((nf+1)/2) * (W/nf + 0.29)'"
as="'int((nf+2)/2) * W/nf * 0.29'" 
ps="'2*int((nf+2)/2) * (W/nf + 0.29)'"
nrd="'0.29 / W'" nrs="'0.29 / W'"
sa=0 sb=0 sd=0
model=nfet_01v8
spiceprefix=X
}
C {madvlsi/nmos3.sym} 1400 -2030 1 0 {name=M2j
L=0.5
W=0.75
body=GND
nf=1
mult=1
ad="'int((nf+1)/2) * W/nf * 0.29'" 
pd="'2*int((nf+1)/2) * (W/nf + 0.29)'"
as="'int((nf+2)/2) * W/nf * 0.29'" 
ps="'2*int((nf+2)/2) * (W/nf + 0.29)'"
nrd="'0.29 / W'" nrs="'0.29 / W'"
sa=0 sb=0 sd=0
model=nfet_01v8
spiceprefix=X
}
C {madvlsi/nmos3.sym} 1480 -2030 1 0 {name=M2k
L=0.5
W=0.75
body=GND
nf=1
mult=1
ad="'int((nf+1)/2) * W/nf * 0.29'" 
pd="'2*int((nf+1)/2) * (W/nf + 0.29)'"
as="'int((nf+2)/2) * W/nf * 0.29'" 
ps="'2*int((nf+2)/2) * (W/nf + 0.29)'"
nrd="'0.29 / W'" nrs="'0.29 / W'"
sa=0 sb=0 sd=0
model=nfet_01v8
spiceprefix=X
}
C {madvlsi/nmos3.sym} 1560 -2030 1 0 {name=M2l
L=0.5
W=0.75
body=GND
nf=1
mult=1
ad="'int((nf+1)/2) * W/nf * 0.29'" 
pd="'2*int((nf+1)/2) * (W/nf + 0.29)'"
as="'int((nf+2)/2) * W/nf * 0.29'" 
ps="'2*int((nf+2)/2) * (W/nf + 0.29)'"
nrd="'0.29 / W'" nrs="'0.29 / W'"
sa=0 sb=0 sd=0
model=nfet_01v8
spiceprefix=X
}
C {madvlsi/nmos3.sym} 1640 -2030 1 0 {name=M2m
L=0.5
W=0.75
body=GND
nf=1
mult=1
ad="'int((nf+1)/2) * W/nf * 0.29'" 
pd="'2*int((nf+1)/2) * (W/nf + 0.29)'"
as="'int((nf+2)/2) * W/nf * 0.29'" 
ps="'2*int((nf+2)/2) * (W/nf + 0.29)'"
nrd="'0.29 / W'" nrs="'0.29 / W'"
sa=0 sb=0 sd=0
model=nfet_01v8
spiceprefix=X
}
C {madvlsi/nmos3.sym} 1720 -2030 1 0 {name=M2n
L=0.5
W=0.75
body=GND
nf=1
mult=1
ad="'int((nf+1)/2) * W/nf * 0.29'" 
pd="'2*int((nf+1)/2) * (W/nf + 0.29)'"
as="'int((nf+2)/2) * W/nf * 0.29'" 
ps="'2*int((nf+2)/2) * (W/nf + 0.29)'"
nrd="'0.29 / W'" nrs="'0.29 / W'"
sa=0 sb=0 sd=0
model=nfet_01v8
spiceprefix=X
}
C {madvlsi/nmos3.sym} 1800 -2030 1 0 {name=M2o
L=0.5
W=0.75
body=GND
nf=1
mult=1
ad="'int((nf+1)/2) * W/nf * 0.29'" 
pd="'2*int((nf+1)/2) * (W/nf + 0.29)'"
as="'int((nf+2)/2) * W/nf * 0.29'" 
ps="'2*int((nf+2)/2) * (W/nf + 0.29)'"
nrd="'0.29 / W'" nrs="'0.29 / W'"
sa=0 sb=0 sd=0
model=nfet_01v8
spiceprefix=X
}
C {madvlsi/nmos3.sym} 1880 -2030 1 0 {name=M2p
L=0.5
W=0.75
body=GND
nf=1
mult=1
ad="'int((nf+1)/2) * W/nf * 0.29'" 
pd="'2*int((nf+1)/2) * (W/nf + 0.29)'"
as="'int((nf+2)/2) * W/nf * 0.29'" 
ps="'2*int((nf+2)/2) * (W/nf + 0.29)'"
nrd="'0.29 / W'" nrs="'0.29 / W'"
sa=0 sb=0 sd=0
model=nfet_01v8
spiceprefix=X
}
C {madvlsi/nmos3.sym} 1960 -2030 1 0 {name=Md6
L=0.5
W=0.75
body=GND
nf=1
mult=1
ad="'int((nf+1)/2) * W/nf * 0.29'" 
pd="'2*int((nf+1)/2) * (W/nf + 0.29)'"
as="'int((nf+2)/2) * W/nf * 0.29'" 
ps="'2*int((nf+2)/2) * (W/nf + 0.29)'"
nrd="'0.29 / W'" nrs="'0.29 / W'"
sa=0 sb=0 sd=0
model=nfet_01v8
spiceprefix=X
}
C {madvlsi/nmos3.sym} 600 -2030 1 0 {name=Md5
L=0.5
W=0.75
body=GND
nf=1
mult=1
ad="'int((nf+1)/2) * W/nf * 0.29'" 
pd="'2*int((nf+1)/2) * (W/nf + 0.29)'"
as="'int((nf+2)/2) * W/nf * 0.29'" 
ps="'2*int((nf+2)/2) * (W/nf + 0.29)'"
nrd="'0.29 / W'" nrs="'0.29 / W'"
sa=0 sb=0 sd=0
model=nfet_01v8
spiceprefix=X
}
C {madvlsi/pmos3.sym} 1700 -1220 3 0 {name=M5a
L=0.5
W=3
body=VDD
nf=1
mult=1
ad="'int((nf+1)/2) * W/nf * 0.29'" 
pd="'2*int((nf+1)/2) * (W/nf + 0.29)'"
as="'int((nf+2)/2) * W/nf * 0.29'" 
ps="'2*int((nf+2)/2) * (W/nf + 0.29)'"
nrd="'0.29 / W'" nrs="'0.29 / W'"
sa=0 sb=0 sd=0
model=pfet_01v8
spiceprefix=X
}
C {madvlsi/pmos3.sym} 1780 -1220 3 0 {name=M6a
L=0.5
W=3
body=VDD
nf=1
mult=1
ad="'int((nf+1)/2) * W/nf * 0.29'" 
pd="'2*int((nf+1)/2) * (W/nf + 0.29)'"
as="'int((nf+2)/2) * W/nf * 0.29'" 
ps="'2*int((nf+2)/2) * (W/nf + 0.29)'"
nrd="'0.29 / W'" nrs="'0.29 / W'"
sa=0 sb=0 sd=0
model=pfet_01v8
spiceprefix=X
}
C {madvlsi/pmos3.sym} 1860 -1220 3 0 {name=M6b
L=0.5
W=3
body=VDD
nf=1
mult=1
ad="'int((nf+1)/2) * W/nf * 0.29'" 
pd="'2*int((nf+1)/2) * (W/nf + 0.29)'"
as="'int((nf+2)/2) * W/nf * 0.29'" 
ps="'2*int((nf+2)/2) * (W/nf + 0.29)'"
nrd="'0.29 / W'" nrs="'0.29 / W'"
sa=0 sb=0 sd=0
model=pfet_01v8
spiceprefix=X
}
C {madvlsi/pmos3.sym} 1940 -1220 3 0 {name=M5b
L=0.5
W=3
body=VDD
nf=1
mult=1
ad="'int((nf+1)/2) * W/nf * 0.29'" 
pd="'2*int((nf+1)/2) * (W/nf + 0.29)'"
as="'int((nf+2)/2) * W/nf * 0.29'" 
ps="'2*int((nf+2)/2) * (W/nf + 0.29)'"
nrd="'0.29 / W'" nrs="'0.29 / W'"
sa=0 sb=0 sd=0
model=pfet_01v8
spiceprefix=X
}
C {madvlsi/pmos3.sym} 2020 -1220 3 0 {name=M5c
L=0.5
W=3
body=VDD
nf=1
mult=1
ad="'int((nf+1)/2) * W/nf * 0.29'" 
pd="'2*int((nf+1)/2) * (W/nf + 0.29)'"
as="'int((nf+2)/2) * W/nf * 0.29'" 
ps="'2*int((nf+2)/2) * (W/nf + 0.29)'"
nrd="'0.29 / W'" nrs="'0.29 / W'"
sa=0 sb=0 sd=0
model=pfet_01v8
spiceprefix=X
}
C {madvlsi/pmos3.sym} 2100 -1220 3 0 {name=M6c
L=0.5
W=3
body=VDD
nf=1
mult=1
ad="'int((nf+1)/2) * W/nf * 0.29'" 
pd="'2*int((nf+1)/2) * (W/nf + 0.29)'"
as="'int((nf+2)/2) * W/nf * 0.29'" 
ps="'2*int((nf+2)/2) * (W/nf + 0.29)'"
nrd="'0.29 / W'" nrs="'0.29 / W'"
sa=0 sb=0 sd=0
model=pfet_01v8
spiceprefix=X
}
C {madvlsi/pmos3.sym} 2180 -1220 3 0 {name=M6d
L=0.5
W=3
body=VDD
nf=1
mult=1
ad="'int((nf+1)/2) * W/nf * 0.29'" 
pd="'2*int((nf+1)/2) * (W/nf + 0.29)'"
as="'int((nf+2)/2) * W/nf * 0.29'" 
ps="'2*int((nf+2)/2) * (W/nf + 0.29)'"
nrd="'0.29 / W'" nrs="'0.29 / W'"
sa=0 sb=0 sd=0
model=pfet_01v8
spiceprefix=X
}
C {madvlsi/pmos3.sym} 2260 -1220 3 0 {name=M5d
L=0.5
W=3
body=VDD
nf=1
mult=1
ad="'int((nf+1)/2) * W/nf * 0.29'" 
pd="'2*int((nf+1)/2) * (W/nf + 0.29)'"
as="'int((nf+2)/2) * W/nf * 0.29'" 
ps="'2*int((nf+2)/2) * (W/nf + 0.29)'"
nrd="'0.29 / W'" nrs="'0.29 / W'"
sa=0 sb=0 sd=0
model=pfet_01v8
spiceprefix=X
}
C {madvlsi/pmos3.sym} 1620 -1220 3 0 {name=Md7
L=0.5
W=3
body=VDD
nf=1
mult=1
ad="'int((nf+1)/2) * W/nf * 0.29'" 
pd="'2*int((nf+1)/2) * (W/nf + 0.29)'"
as="'int((nf+2)/2) * W/nf * 0.29'" 
ps="'2*int((nf+2)/2) * (W/nf + 0.29)'"
nrd="'0.29 / W'" nrs="'0.29 / W'"
sa=0 sb=0 sd=0
model=pfet_01v8
spiceprefix=X
}
C {madvlsi/pmos3.sym} 2340 -1220 3 0 {name=Md8
L=0.5
W=3
body=VDD
nf=1
mult=1
ad="'int((nf+1)/2) * W/nf * 0.29'" 
pd="'2*int((nf+1)/2) * (W/nf + 0.29)'"
as="'int((nf+2)/2) * W/nf * 0.29'" 
ps="'2*int((nf+2)/2) * (W/nf + 0.29)'"
nrd="'0.29 / W'" nrs="'0.29 / W'"
sa=0 sb=0 sd=0
model=pfet_01v8
spiceprefix=X
}
C {madvlsi/pmos3.sym} 510 -1220 3 0 {name=M7a
L=0.5
W=3
body=VDD
nf=1
mult=1
ad="'int((nf+1)/2) * W/nf * 0.29'" 
pd="'2*int((nf+1)/2) * (W/nf + 0.29)'"
as="'int((nf+2)/2) * W/nf * 0.29'" 
ps="'2*int((nf+2)/2) * (W/nf + 0.29)'"
nrd="'0.29 / W'" nrs="'0.29 / W'"
sa=0 sb=0 sd=0
model=pfet_01v8
spiceprefix=X
}
C {madvlsi/pmos3.sym} 590 -1220 3 0 {name=M8a
L=0.5
W=3
body=VDD
nf=1
mult=1
ad="'int((nf+1)/2) * W/nf * 0.29'" 
pd="'2*int((nf+1)/2) * (W/nf + 0.29)'"
as="'int((nf+2)/2) * W/nf * 0.29'" 
ps="'2*int((nf+2)/2) * (W/nf + 0.29)'"
nrd="'0.29 / W'" nrs="'0.29 / W'"
sa=0 sb=0 sd=0
model=pfet_01v8
spiceprefix=X
}
C {madvlsi/pmos3.sym} 670 -1220 3 0 {name=M8b
L=0.5
W=3
body=VDD
nf=1
mult=1
ad="'int((nf+1)/2) * W/nf * 0.29'" 
pd="'2*int((nf+1)/2) * (W/nf + 0.29)'"
as="'int((nf+2)/2) * W/nf * 0.29'" 
ps="'2*int((nf+2)/2) * (W/nf + 0.29)'"
nrd="'0.29 / W'" nrs="'0.29 / W'"
sa=0 sb=0 sd=0
model=pfet_01v8
spiceprefix=X
}
C {madvlsi/pmos3.sym} 750 -1220 3 0 {name=M7b
L=0.5
W=3
body=VDD
nf=1
mult=1
ad="'int((nf+1)/2) * W/nf * 0.29'" 
pd="'2*int((nf+1)/2) * (W/nf + 0.29)'"
as="'int((nf+2)/2) * W/nf * 0.29'" 
ps="'2*int((nf+2)/2) * (W/nf + 0.29)'"
nrd="'0.29 / W'" nrs="'0.29 / W'"
sa=0 sb=0 sd=0
model=pfet_01v8
spiceprefix=X
}
C {madvlsi/pmos3.sym} 830 -1220 3 0 {name=M7c
L=0.5
W=3
body=VDD
nf=1
mult=1
ad="'int((nf+1)/2) * W/nf * 0.29'" 
pd="'2*int((nf+1)/2) * (W/nf + 0.29)'"
as="'int((nf+2)/2) * W/nf * 0.29'" 
ps="'2*int((nf+2)/2) * (W/nf + 0.29)'"
nrd="'0.29 / W'" nrs="'0.29 / W'"
sa=0 sb=0 sd=0
model=pfet_01v8
spiceprefix=X
}
C {madvlsi/pmos3.sym} 910 -1220 3 0 {name=M8c
L=0.5
W=3
body=VDD
nf=1
mult=1
ad="'int((nf+1)/2) * W/nf * 0.29'" 
pd="'2*int((nf+1)/2) * (W/nf + 0.29)'"
as="'int((nf+2)/2) * W/nf * 0.29'" 
ps="'2*int((nf+2)/2) * (W/nf + 0.29)'"
nrd="'0.29 / W'" nrs="'0.29 / W'"
sa=0 sb=0 sd=0
model=pfet_01v8
spiceprefix=X
}
C {madvlsi/pmos3.sym} 990 -1220 3 0 {name=M8d
L=0.5
W=3
body=VDD
nf=1
mult=1
ad="'int((nf+1)/2) * W/nf * 0.29'" 
pd="'2*int((nf+1)/2) * (W/nf + 0.29)'"
as="'int((nf+2)/2) * W/nf * 0.29'" 
ps="'2*int((nf+2)/2) * (W/nf + 0.29)'"
nrd="'0.29 / W'" nrs="'0.29 / W'"
sa=0 sb=0 sd=0
model=pfet_01v8
spiceprefix=X
}
C {madvlsi/pmos3.sym} 1070 -1220 3 0 {name=M7d
L=0.5
W=3
body=VDD
nf=1
mult=1
ad="'int((nf+1)/2) * W/nf * 0.29'" 
pd="'2*int((nf+1)/2) * (W/nf + 0.29)'"
as="'int((nf+2)/2) * W/nf * 0.29'" 
ps="'2*int((nf+2)/2) * (W/nf + 0.29)'"
nrd="'0.29 / W'" nrs="'0.29 / W'"
sa=0 sb=0 sd=0
model=pfet_01v8
spiceprefix=X
}
C {madvlsi/pmos3.sym} 430 -1220 3 0 {name=Md9
L=0.5
W=3
body=VDD
nf=1
mult=1
ad="'int((nf+1)/2) * W/nf * 0.29'" 
pd="'2*int((nf+1)/2) * (W/nf + 0.29)'"
as="'int((nf+2)/2) * W/nf * 0.29'" 
ps="'2*int((nf+2)/2) * (W/nf + 0.29)'"
nrd="'0.29 / W'" nrs="'0.29 / W'"
sa=0 sb=0 sd=0
model=pfet_01v8
spiceprefix=X
}
C {madvlsi/pmos3.sym} 1150 -1220 3 0 {name=Md10
L=0.5
W=3
body=VDD
nf=1
mult=1
ad="'int((nf+1)/2) * W/nf * 0.29'" 
pd="'2*int((nf+1)/2) * (W/nf + 0.29)'"
as="'int((nf+2)/2) * W/nf * 0.29'" 
ps="'2*int((nf+2)/2) * (W/nf + 0.29)'"
nrd="'0.29 / W'" nrs="'0.29 / W'"
sa=0 sb=0 sd=0
model=pfet_01v8
spiceprefix=X
}
C {madvlsi/pmos3.sym} 670 -960 3 0 {name=M1a
L=0.5
W=0.75
body=VDD
nf=1
mult=1
ad="'int((nf+1)/2) * W/nf * 0.29'" 
pd="'2*int((nf+1)/2) * (W/nf + 0.29)'"
as="'int((nf+2)/2) * W/nf * 0.29'" 
ps="'2*int((nf+2)/2) * (W/nf + 0.29)'"
nrd="'0.29 / W'" nrs="'0.29 / W'"
sa=0 sb=0 sd=0
model=pfet_01v8
spiceprefix=X
}
C {madvlsi/pmos3.sym} 750 -960 3 0 {name=M1b
L=0.5
W=0.75
body=VDD
nf=1
mult=1
ad="'int((nf+1)/2) * W/nf * 0.29'" 
pd="'2*int((nf+1)/2) * (W/nf + 0.29)'"
as="'int((nf+2)/2) * W/nf * 0.29'" 
ps="'2*int((nf+2)/2) * (W/nf + 0.29)'"
nrd="'0.29 / W'" nrs="'0.29 / W'"
sa=0 sb=0 sd=0
model=pfet_01v8
spiceprefix=X
}
C {madvlsi/pmos3.sym} 830 -960 3 0 {name=M1c
L=0.5
W=0.75
body=VDD
nf=1
mult=1
ad="'int((nf+1)/2) * W/nf * 0.29'" 
pd="'2*int((nf+1)/2) * (W/nf + 0.29)'"
as="'int((nf+2)/2) * W/nf * 0.29'" 
ps="'2*int((nf+2)/2) * (W/nf + 0.29)'"
nrd="'0.29 / W'" nrs="'0.29 / W'"
sa=0 sb=0 sd=0
model=pfet_01v8
spiceprefix=X
}
C {madvlsi/pmos3.sym} 910 -960 3 0 {name=M1d
L=0.5
W=0.75
body=VDD
nf=1
mult=1
ad="'int((nf+1)/2) * W/nf * 0.29'" 
pd="'2*int((nf+1)/2) * (W/nf + 0.29)'"
as="'int((nf+2)/2) * W/nf * 0.29'" 
ps="'2*int((nf+2)/2) * (W/nf + 0.29)'"
nrd="'0.29 / W'" nrs="'0.29 / W'"
sa=0 sb=0 sd=0
model=pfet_01v8
spiceprefix=X
}
C {madvlsi/pmos3.sym} 990 -960 3 0 {name=M1e
L=0.5
W=0.75
body=VDD
nf=1
mult=1
ad="'int((nf+1)/2) * W/nf * 0.29'" 
pd="'2*int((nf+1)/2) * (W/nf + 0.29)'"
as="'int((nf+2)/2) * W/nf * 0.29'" 
ps="'2*int((nf+2)/2) * (W/nf + 0.29)'"
nrd="'0.29 / W'" nrs="'0.29 / W'"
sa=0 sb=0 sd=0
model=pfet_01v8
spiceprefix=X
}
C {madvlsi/pmos3.sym} 1070 -960 3 0 {name=M1f
L=0.5
W=0.75
body=VDD
nf=1
mult=1
ad="'int((nf+1)/2) * W/nf * 0.29'" 
pd="'2*int((nf+1)/2) * (W/nf + 0.29)'"
as="'int((nf+2)/2) * W/nf * 0.29'" 
ps="'2*int((nf+2)/2) * (W/nf + 0.29)'"
nrd="'0.29 / W'" nrs="'0.29 / W'"
sa=0 sb=0 sd=0
model=pfet_01v8
spiceprefix=X
}
C {madvlsi/pmos3.sym} 1150 -960 3 0 {name=M1g
L=0.5
W=0.75
body=VDD
nf=1
mult=1
ad="'int((nf+1)/2) * W/nf * 0.29'" 
pd="'2*int((nf+1)/2) * (W/nf + 0.29)'"
as="'int((nf+2)/2) * W/nf * 0.29'" 
ps="'2*int((nf+2)/2) * (W/nf + 0.29)'"
nrd="'0.29 / W'" nrs="'0.29 / W'"
sa=0 sb=0 sd=0
model=pfet_01v8
spiceprefix=X
}
C {madvlsi/pmos3.sym} 1230 -960 3 0 {name=M1h
L=0.5
W=0.75
body=VDD
nf=1
mult=1
ad="'int((nf+1)/2) * W/nf * 0.29'" 
pd="'2*int((nf+1)/2) * (W/nf + 0.29)'"
as="'int((nf+2)/2) * W/nf * 0.29'" 
ps="'2*int((nf+2)/2) * (W/nf + 0.29)'"
nrd="'0.29 / W'" nrs="'0.29 / W'"
sa=0 sb=0 sd=0
model=pfet_01v8
spiceprefix=X
}
C {madvlsi/pmos3.sym} 1310 -960 3 0 {name=M1i
L=0.5
W=0.75
body=VDD
nf=1
mult=1
ad="'int((nf+1)/2) * W/nf * 0.29'" 
pd="'2*int((nf+1)/2) * (W/nf + 0.29)'"
as="'int((nf+2)/2) * W/nf * 0.29'" 
ps="'2*int((nf+2)/2) * (W/nf + 0.29)'"
nrd="'0.29 / W'" nrs="'0.29 / W'"
sa=0 sb=0 sd=0
model=pfet_01v8
spiceprefix=X
}
C {madvlsi/pmos3.sym} 1390 -960 3 0 {name=M1j
L=0.5
W=0.75
body=VDD
nf=1
mult=1
ad="'int((nf+1)/2) * W/nf * 0.29'" 
pd="'2*int((nf+1)/2) * (W/nf + 0.29)'"
as="'int((nf+2)/2) * W/nf * 0.29'" 
ps="'2*int((nf+2)/2) * (W/nf + 0.29)'"
nrd="'0.29 / W'" nrs="'0.29 / W'"
sa=0 sb=0 sd=0
model=pfet_01v8
spiceprefix=X
}
C {madvlsi/pmos3.sym} 1470 -960 3 0 {name=M1k
L=0.5
W=0.75
body=VDD
nf=1
mult=1
ad="'int((nf+1)/2) * W/nf * 0.29'" 
pd="'2*int((nf+1)/2) * (W/nf + 0.29)'"
as="'int((nf+2)/2) * W/nf * 0.29'" 
ps="'2*int((nf+2)/2) * (W/nf + 0.29)'"
nrd="'0.29 / W'" nrs="'0.29 / W'"
sa=0 sb=0 sd=0
model=pfet_01v8
spiceprefix=X
}
C {madvlsi/pmos3.sym} 1550 -960 3 0 {name=M1l
L=0.5
W=0.75
body=VDD
nf=1
mult=1
ad="'int((nf+1)/2) * W/nf * 0.29'" 
pd="'2*int((nf+1)/2) * (W/nf + 0.29)'"
as="'int((nf+2)/2) * W/nf * 0.29'" 
ps="'2*int((nf+2)/2) * (W/nf + 0.29)'"
nrd="'0.29 / W'" nrs="'0.29 / W'"
sa=0 sb=0 sd=0
model=pfet_01v8
spiceprefix=X
}
C {madvlsi/pmos3.sym} 1630 -960 3 0 {name=M1m
L=0.5
W=0.75
body=VDD
nf=1
mult=1
ad="'int((nf+1)/2) * W/nf * 0.29'" 
pd="'2*int((nf+1)/2) * (W/nf + 0.29)'"
as="'int((nf+2)/2) * W/nf * 0.29'" 
ps="'2*int((nf+2)/2) * (W/nf + 0.29)'"
nrd="'0.29 / W'" nrs="'0.29 / W'"
sa=0 sb=0 sd=0
model=pfet_01v8
spiceprefix=X
}
C {madvlsi/pmos3.sym} 1710 -960 3 0 {name=M1n
L=0.5
W=0.75
body=VDD
nf=1
mult=1
ad="'int((nf+1)/2) * W/nf * 0.29'" 
pd="'2*int((nf+1)/2) * (W/nf + 0.29)'"
as="'int((nf+2)/2) * W/nf * 0.29'" 
ps="'2*int((nf+2)/2) * (W/nf + 0.29)'"
nrd="'0.29 / W'" nrs="'0.29 / W'"
sa=0 sb=0 sd=0
model=pfet_01v8
spiceprefix=X
}
C {madvlsi/pmos3.sym} 1790 -960 3 0 {name=M1o
L=0.5
W=0.75
body=VDD
nf=1
mult=1
ad="'int((nf+1)/2) * W/nf * 0.29'" 
pd="'2*int((nf+1)/2) * (W/nf + 0.29)'"
as="'int((nf+2)/2) * W/nf * 0.29'" 
ps="'2*int((nf+2)/2) * (W/nf + 0.29)'"
nrd="'0.29 / W'" nrs="'0.29 / W'"
sa=0 sb=0 sd=0
model=pfet_01v8
spiceprefix=X
}
C {madvlsi/pmos3.sym} 1870 -960 3 0 {name=M1p
L=0.5
W=0.75
body=VDD
nf=1
mult=1
ad="'int((nf+1)/2) * W/nf * 0.29'" 
pd="'2*int((nf+1)/2) * (W/nf + 0.29)'"
as="'int((nf+2)/2) * W/nf * 0.29'" 
ps="'2*int((nf+2)/2) * (W/nf + 0.29)'"
nrd="'0.29 / W'" nrs="'0.29 / W'"
sa=0 sb=0 sd=0
model=pfet_01v8
spiceprefix=X
}
C {madvlsi/pmos3.sym} 590 -960 3 0 {name=Md11
L=0.5
W=0.75
body=VDD
nf=1
mult=1
ad="'int((nf+1)/2) * W/nf * 0.29'" 
pd="'2*int((nf+1)/2) * (W/nf + 0.29)'"
as="'int((nf+2)/2) * W/nf * 0.29'" 
ps="'2*int((nf+2)/2) * (W/nf + 0.29)'"
nrd="'0.29 / W'" nrs="'0.29 / W'"
sa=0 sb=0 sd=0
model=pfet_01v8
spiceprefix=X
}
C {madvlsi/pmos3.sym} 1950 -960 3 0 {name=Md12
L=0.5
W=0.75
body=VDD
nf=1
mult=1
ad="'int((nf+1)/2) * W/nf * 0.29'" 
pd="'2*int((nf+1)/2) * (W/nf + 0.29)'"
as="'int((nf+2)/2) * W/nf * 0.29'" 
ps="'2*int((nf+2)/2) * (W/nf + 0.29)'"
nrd="'0.29 / W'" nrs="'0.29 / W'"
sa=0 sb=0 sd=0
model=pfet_01v8
spiceprefix=X
}
C {devices/iopin.sym} 400 -1890 2 0 {name=p3 lab=I1p}
C {devices/iopin.sym} 310 -1090 2 0 {name=p4 lab=I1n}
C {devices/iopin.sym} 360 -1680 2 0 {name=p5 lab=Vbn}
C {devices/iopin.sym} 310 -1120 2 0 {name=p6 lab=Vbp}
C {devices/opin.sym} 2240 -1590 0 0 {name=p7 lab=Vcn}
C {devices/opin.sym} 2250 -1450 0 0 {name=p8 lab=Vcp}
C {devices/iopin.sym} 270 -990 2 0 {name=p1 lab=VP}
C {devices/iopin.sym} 400 -1960 2 0 {name=p2 lab=VN}
